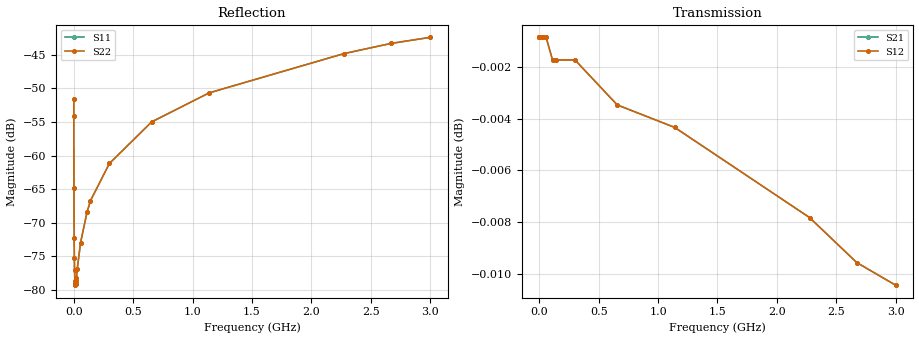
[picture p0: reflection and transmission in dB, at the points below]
! S-Parameter Data Generated by TDK Corporation
! Copyright(C) 2022 TDK Corporation.
! All Rights Reserved.
! TDK P/N: CLLC1AX7S0G225M050AC (Multilayer Ceramic Chip Capacitor)
! Property: C=2.2uF
! Size(LxWxT): 1.6x0.8x0.5mm
! Model Type: s2p (Touchstone File Format Version 1.0)
! Frequency: DC=Yes Start=0.3MHz Stop=3000MHz 402points Log-sweep
! Model Generated on Apr. 15, 2022
! Port Assignments:
!  1 ---| |--- 2
! Applicable Conditions:
!  Temperature = 25 degC
!  DC Bias Voltage = 0 V
!  Small Signal Operation
! Terms and conditions regarding TDK Simulation Models
! (1)This simulation model is being provided solely for informational purposes. Please refer to the specifications of the products in terms of detailed characteristics of such products.
! (2)In no event shall TDK Corporation of any of its subsidiaries be liable for any loss or damage arising, directly or indirectly,
!  From any information contained in this simulation model, including, but not limited to loss or damages arising from any inaccuracies, omissions or errors in connection with such information.
! (3)Any and all copyrights on this simulation model are owned by TDK Corporation.
!  Duplication or redistribution of this simulation model without prior written permission from TDK Corporation is prohibited.
! (4)This simulation model is subject to any modification or change without any prior notice.
! (5)Neither TDK Corporation nor any of its subsidiaries shall make any warranty, express or implied,
!  Including but not limited to the correctness, implied warranties of merchantability and fitness for a particular purpose with respect to this simulation models.
! (6)The use of this simulation model shall be deemed to have consented to the terms and conditions hereof.
# Hz S MA R 50
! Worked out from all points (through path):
!   401 points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, 300 kHz to 3 GHz, reference 50 ohm
!   highest |S21| = 0.00 dB at 4.865 MHz (marker M1); lowest = 0.0 dB at 3 GHz (marker M2)
!   lowest |S11| = -79.3 dB at 13.1 MHz (marker M3), VSWR 1.00, Z = 50 - j0.000805 ohm
!   |S11| at or under -10 dB: start of sweep to end of sweep
!   |S22| runs from -79.3 to -42.4 dB; largest |S21 - S12| = 0
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300000  0.002654 -87.0  0.9999 0.2  0.9999 0.2  0.002654 -87.0
404689  0.001971 -86.3  0.9999 0.1  0.9999 0.1  0.001971 -86.3
1403210  0.0005711 -79.2  0.9999 0.0  0.9999 0.0  0.0005711 -79.2
3366060  0.0002437 -65.0  0.9999 0.0  0.9999 0.0  0.0002437 -65.0
4865430  0.000174 -54.3  0.9999 0.0  0.9999 0.0  0.000174 -54.3
6563280  0.0001405 -40.9  0.9999 0.0  0.9999 0.0  0.0001405 -40.9
9270890  0.0001164 -23.8  0.9999 0.0  0.9999 0.0  0.0001164 -23.8
1.11461e7  0.0001107 -14.0  0.9999 0.0  0.9999 0.0  0.0001107 -14.0
1.30955e7  0.0001088 -4.2  0.9999 0.0  0.9999 0.0  0.0001088 -4.2
1.6111e7  0.0001112 6.8  0.9999 -0.0  0.9999 -0.0  0.0001112 6.8
1.98208e7  0.0001177 17.6  0.9999 -0.0  0.9999 -0.0  0.0001177 17.6
2.22393e7  0.0001228 22.8  0.9999 -0.0  0.9999 -0.0  0.0001228 22.8
3e7  0.0001444 35.3  0.9999 -0.0  0.9999 -0.0  0.0001444 35.3
5.71638e7  0.0002248 53.3  0.9999 -0.0  0.9999 -0.0  0.0002248 53.3
1.11461e8  0.0003785 64.7  0.9998 -0.0  0.9998 -0.0  0.0003785 64.7
1.40321e8  0.0004607 67.6  0.9998 -0.0  0.9998 -0.0  0.0004607 67.6
3e8  0.0008729 74.5  0.9998 -0.0  0.9998 -0.0  0.0008729 74.5
6.56328e8  0.00178 78.6  0.9996 -0.1  0.9996 -0.1  0.00178 78.6
1.14057e9  0.002925 80.3  0.9995 -0.2  0.9995 -0.2  0.002925 80.3
2.27573e9  0.005728 80.7  0.9991 -0.3  0.9991 -0.3  0.005728 80.7
2.67375e9  0.006822 80.9  0.9989 -0.4  0.9989 -0.4  0.006822 80.9
3e9  0.007561 80.7  0.9988 -0.4  0.9988 -0.4  0.007561 80.7
